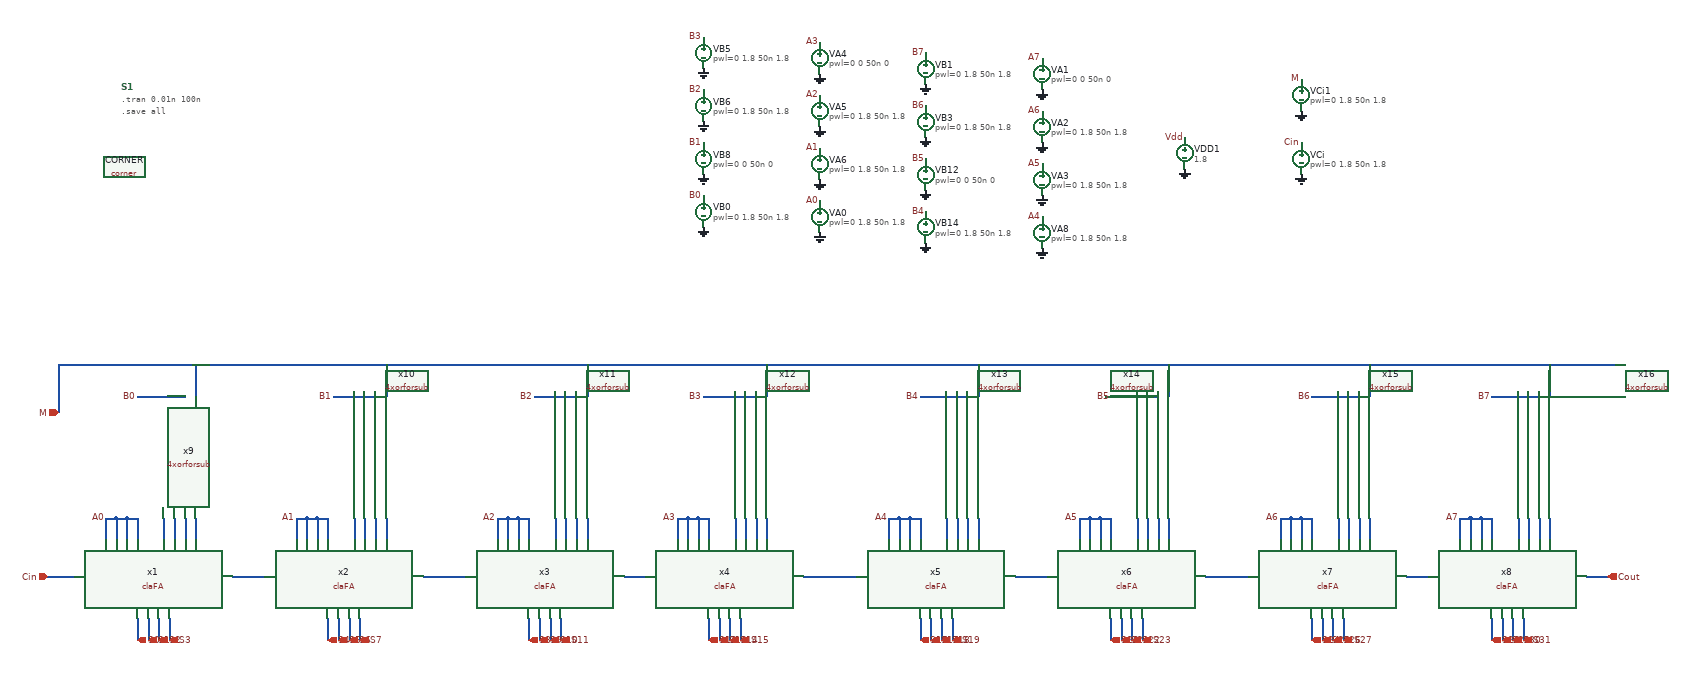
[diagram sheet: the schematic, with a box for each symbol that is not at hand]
v {xschem version=3.4.5 file_version=1.2
}
G {}
K {}
V {}
S {}
E {}
B 2 470 -1465 1270 -1065 {flags=graph
y1=0
y2=2
ypos1=-0.67313425
ypos2=1.3268657

subdivy=1
unity=1
x1=-3.0826129e-09
x2=9.6917371e-08


xlabmag=1.0
ylabmag=1.0


dataset=-1
unitx=1
logx=0
logy=0
divx=10
divy=5
subdivx=1
digital=1



color="11 11 11"
node="a;a0,a,a,a,a1,a1,a1,a1,a2,a2,a2,a2,a3,a3,a3,a3,a4,a4,a4,a4,a5,a5,a5,a5,a6,a6,a6,a6,a7,a7,a7,a7
b;b0,b0,b0,b0,b1,b1,b1,b1,b2,b2,b2,b2,b4,b3,b3,b3,b4,b4,b4,b4,b5,b5,b5,b5,b6,b6,b6,b6,b7,b7,b7,b7
sub;s0,s1,s2,s3,s4,s5,s6,s7,s8,s9,s10,s11,s12,s13,s14,s15,s16,s17,s18,s19,s20,s21,s22,s23,s24,s25,s26,s27,s28,s29,s30,s31"}
B 2 480 -2035 1280 -1635 {flags=graph
y1=0
y2=2
ypos1=1.1268657
ypos2=3.1268657

subdivy=1
unity=1
x1=-3.0826129e-09
x2=9.6917371e-08


xlabmag=1.0
ylabmag=1.0


dataset=-1
unitx=1
logx=0
logy=0
divx=10
divy=5
subdivx=1
digital=1




color="4 4 4 4 4 4 4 4 4 4 4 4 4 4 4 4 4 4 4 4 4 4 4 4 4 4 4 4 4 4 4 4"
node="a7
a7
a7
a7
a6
a6
a6
a6
a5
a5
a5
a5
a4
a4
a4
a4
a3
a3
a3
a3
a2
a2
a2
a2
a1
a1
a1
a1
a0
a0
a0
a0"}
N 460 -450 520 -450 {
lab=#net1}
N 820 -450 900 -450 {
lab=#net2}
N 1200 -450 1240 -450 {
lab=#net3}
N 1540 -450 1600 -450 {
lab=#net4}
N 110 -450 160 -450 {
lab=Cin}
N 220 -560 220 -520 {
lab=A0}
N 240 -560 240 -520 {
lab=A0}
N 260 -560 260 -520 {
lab=A0}
N 280 -560 280 -520 {
lab=A0}
N 330 -560 330 -520 {
lab=#net5}
N 350 -560 350 -520 {
lab=#net6}
N 370 -560 370 -520 {
lab=#net7}
N 390 -560 390 -520 {
lab=#net8}
N 580 -560 580 -520 {
lab=A1}
N 600 -560 600 -520 {
lab=A1}
N 620 -560 620 -520 {
lab=A1}
N 640 -560 640 -520 {
lab=A1}
N 690 -560 690 -520 {
lab=#net9}
N 710 -560 710 -520 {
lab=#net10}
N 730 -560 730 -520 {
lab=#net11}
N 750 -560 750 -520 {
lab=#net12}
N 640 -370 640 -330 {
lab=S4}
N 660 -370 660 -330 {
lab=S5}
N 680 -370 680 -330 {
lab=S6}
N 700 -370 700 -330 {
lab=S7}
N 280 -370 280 -330 {
lab=S0}
N 300 -370 300 -330 {
lab=S1}
N 320 -370 320 -330 {
lab=S2}
N 340 -370 340 -330 {
lab=S3}
N 960 -560 960 -520 {
lab=A2}
N 980 -560 980 -520 {
lab=A2}
N 1000 -560 1000 -520 {
lab=A2}
N 1020 -560 1020 -520 {
lab=A2}
N 1070 -560 1070 -520 {
lab=#net13}
N 1090 -560 1090 -520 {
lab=#net14}
N 1110 -560 1110 -520 {
lab=#net15}
N 1130 -560 1130 -520 {
lab=#net16}
N 1300 -560 1300 -520 {
lab=A3}
N 1320 -560 1320 -520 {
lab=A3}
N 1340 -560 1340 -520 {
lab=A3}
N 1360 -560 1360 -520 {
lab=A3}
N 1410 -560 1410 -520 {
lab=#net17}
N 1430 -560 1430 -520 {
lab=#net18}
N 1450 -560 1450 -520 {
lab=#net19}
N 1470 -560 1470 -520 {
lab=#net20}
N 1020 -370 1020 -330 {
lab=S8}
N 1040 -370 1040 -330 {
lab=S9}
N 1060 -370 1060 -330 {
lab=S10}
N 1080 -370 1080 -330 {
lab=S11}
N 1360 -370 1360 -330 {
lab=S12}
N 1380 -370 1380 -330 {
lab=S13}
N 1400 -370 1400 -330 {
lab=S14}
N 1420 -370 1420 -330 {
lab=S15}
N 260 -560 280 -560 {
lab=A0}
N 240 -560 260 -560 {
lab=A0}
N 220 -560 240 -560 {
lab=A0}
N 580 -560 600 -560 {
lab=A1}
N 600 -560 620 -560 {
lab=A1}
N 620 -560 640 -560 {
lab=A1}
N 960 -560 980 -560 {
lab=A2}
N 980 -560 1000 -560 {
lab=A2}
N 1000 -560 1020 -560 {
lab=A2}
N 1300 -560 1320 -560 {
lab=A3}
N 1320 -560 1340 -560 {
lab=A3}
N 1340 -560 1360 -560 {
lab=A3}
N 1940 -450 2000 -450 {
lab=#net21}
N 2300 -450 2380 -450 {
lab=#net22}
N 2680 -450 2720 -450 {
lab=#net23}
N 1700 -560 1700 -520 {
lab=A4}
N 1720 -560 1720 -520 {
lab=A4}
N 1740 -560 1740 -520 {
lab=A4}
N 1760 -560 1760 -520 {
lab=A4}
N 1810 -560 1810 -520 {
lab=#net24}
N 1830 -560 1830 -520 {
lab=#net25}
N 1850 -560 1850 -520 {
lab=#net26}
N 1870 -560 1870 -520 {
lab=#net27}
N 2060 -560 2060 -520 {
lab=A5}
N 2080 -560 2080 -520 {
lab=A5}
N 2100 -560 2100 -520 {
lab=A5}
N 2120 -560 2120 -520 {
lab=A5}
N 2170 -560 2170 -520 {
lab=#net28}
N 2190 -560 2190 -520 {
lab=#net29}
N 2210 -560 2210 -520 {
lab=#net30}
N 2230 -560 2230 -520 {
lab=#net31}
N 2120 -370 2120 -330 {
lab=S20}
N 2140 -370 2140 -330 {
lab=S21}
N 2160 -370 2160 -330 {
lab=S22}
N 2180 -370 2180 -330 {
lab=S23}
N 1760 -370 1760 -330 {
lab=S16}
N 1780 -370 1780 -330 {
lab=S17}
N 1800 -370 1800 -330 {
lab=S18}
N 1820 -370 1820 -330 {
lab=S19}
N 2440 -560 2440 -520 {
lab=A6}
N 2460 -560 2460 -520 {
lab=A6}
N 2480 -560 2480 -520 {
lab=A6}
N 2500 -560 2500 -520 {
lab=A6}
N 2550 -560 2550 -520 {
lab=#net32}
N 2570 -560 2570 -520 {
lab=#net33}
N 2590 -560 2590 -520 {
lab=#net34}
N 2610 -560 2610 -520 {
lab=#net35}
N 2780 -560 2780 -520 {
lab=A7}
N 2800 -560 2800 -520 {
lab=A7}
N 2820 -560 2820 -520 {
lab=A7}
N 2840 -560 2840 -520 {
lab=A7}
N 2890 -560 2890 -520 {
lab=#net36}
N 2910 -560 2910 -520 {
lab=#net37}
N 2930 -560 2930 -520 {
lab=#net38}
N 2950 -560 2950 -520 {
lab=#net39}
N 2500 -370 2500 -330 {
lab=S24}
N 2520 -370 2520 -330 {
lab=S25}
N 2540 -370 2540 -330 {
lab=S26}
N 2560 -370 2560 -330 {
lab=S27}
N 2840 -370 2840 -330 {
lab=S28}
N 2860 -370 2860 -330 {
lab=S29}
N 2880 -370 2880 -330 {
lab=S30}
N 2900 -370 2900 -330 {
lab=S31}
N 1740 -560 1760 -560 {
lab=A4}
N 1720 -560 1740 -560 {
lab=A4}
N 1700 -560 1720 -560 {
lab=A4}
N 2060 -560 2080 -560 {
lab=A5}
N 2080 -560 2100 -560 {
lab=A5}
N 2100 -560 2120 -560 {
lab=A5}
N 2440 -560 2460 -560 {
lab=A6}
N 2460 -560 2480 -560 {
lab=A6}
N 2480 -560 2500 -560 {
lab=A6}
N 2780 -560 2800 -560 {
lab=A7}
N 2800 -560 2820 -560 {
lab=A7}
N 2820 -560 2840 -560 {
lab=A7}
N 3020 -450 3060 -450 {
lab=Cout}
N 1600 -450 1640 -450 {
lab=#net4}
N 384 -850 3074 -850 {
lab=M}
N 130 -850 130 -760 {
lab=M}
N 130 -850 380 -850 {
lab=M}
N 380 -850 390 -850 {
lab=M}
N 2950 -850 2950 -790 {
lab=M}
N 2610 -850 2610 -790 {
lab=M}
N 2230 -850 2230 -790 {
lab=M}
N 1870 -850 1870 -790 {
lab=M}
N 1130 -850 1130 -790 {
lab=M}
N 750 -850 750 -790 {
lab=M}
N 390 -850 390 -790 {
lab=M}
N 350 -790 370 -790 {
lab=B0}
N 330 -790 350 -790 {
lab=B0}
N 310 -790 330 -790 {
lab=B0}
N 280 -790 310 -790 {
lab=B0}
N 710 -790 730 -790 {
lab=B1}
N 690 -790 710 -790 {
lab=B1}
N 650 -790 690 -790 {
lab=B1}
N 1030 -790 1110 -790 {
lab=B2}
N 1470 -850 1470 -790 {
lab=M}
N 1350 -790 1450 -790 {
lab=B3}
N 1760 -790 1850 -790 {
lab=B4}
N 2110 -790 2210 -790 {
lab=B5}
N 2500 -790 2590 -790 {
lab=B6}
N 2840 -790 2930 -790 {
lab=B7}
C {claFA.sym} 310 -430 0 0 {name=x1}
C {claFA.sym} 670 -430 0 0 {name=x2}
C {claFA.sym} 1050 -430 0 0 {name=x3}
C {claFA.sym} 1390 -430 0 0 {name=x4}
C {devices/lab_pin.sym} 220 -560 0 0 {name=p1 sig_type=std_logic lab=A0}
C {devices/lab_pin.sym} 580 -560 0 0 {name=p2 sig_type=std_logic lab=A1}
C {devices/lab_pin.sym} 960 -560 0 0 {name=p3 sig_type=std_logic lab=A2}
C {devices/lab_pin.sym} 1300 -560 0 0 {name=p4 sig_type=std_logic lab=A3}
C {devices/lab_pin.sym} 280 -790 0 0 {name=p5 sig_type=std_logic lab=B0}
C {devices/lab_pin.sym} 650 -790 0 0 {name=p6 sig_type=std_logic lab=B1}
C {devices/lab_pin.sym} 1030 -790 0 0 {name=p7 sig_type=std_logic lab=B2}
C {devices/ipin.sym} 110 -450 0 0 {name=p9 sig_type=std_logic lab=Cin}
C {devices/opin.sym} 3060 -450 0 0 {name=p10 sig_type=std_logic lab=Cout}
C {devices/opin.sym} 280 -330 1 0 {name=p11 sig_type=std_logic lab=S0}
C {devices/opin.sym} 300 -330 1 0 {name=p12 sig_type=std_logic lab=S1}
C {devices/opin.sym} 320 -330 1 0 {name=p13 sig_type=std_logic lab=S2}
C {devices/opin.sym} 340 -330 1 0 {name=p14 sig_type=std_logic lab=S3}
C {devices/opin.sym} 640 -330 1 0 {name=p15 sig_type=std_logic lab=S4}
C {devices/opin.sym} 660 -330 1 0 {name=p16 sig_type=std_logic lab=S5}
C {devices/opin.sym} 680 -330 1 0 {name=p17 sig_type=std_logic lab=S6}
C {devices/opin.sym} 700 -330 1 0 {name=p18 sig_type=std_logic lab=S7}
C {devices/opin.sym} 1020 -330 1 0 {name=p19 sig_type=std_logic lab=S8}
C {devices/opin.sym} 1040 -330 1 0 {name=p20 sig_type=std_logic lab=S9}
C {devices/opin.sym} 1060 -330 1 0 {name=p21 sig_type=std_logic lab=S10}
C {devices/opin.sym} 1080 -330 1 0 {name=p22 sig_type=std_logic lab=S11}
C {devices/opin.sym} 1360 -330 1 0 {name=p23 sig_type=std_logic lab=S12}
C {devices/opin.sym} 1380 -330 1 0 {name=p24 sig_type=std_logic lab=S13}
C {devices/opin.sym} 1400 -330 1 0 {name=p25 sig_type=std_logic lab=S14}
C {devices/opin.sym} 1420 -330 1 0 {name=p26 sig_type=std_logic lab=S15}
C {devices/code_shown.sym} 250 -1375 0 0 {name=S1 only_toplevel=false value=".tran 0.01n 100n
.save all"}
C {sky130_fd_pr/corner.sym} 255 -1225 0 0 {name=CORNER only_toplevel=true corner=tt}
C {devices/vsource.sym} 1570 -1430 0 0 {name=VA4 value="pwl=0 0 50n 0" savecurrent=false}
C {devices/lab_pin.sym} 1570 -1460 0 0 {name=p38 sig_type=std_logic lab=A3}
C {devices/vsource.sym} 1570 -1330 0 0 {name=VA5 value="pwl=0 1.8 50n 1.8 " savecurrent=false}
C {devices/lab_pin.sym} 1570 -1360 0 0 {name=p39 sig_type=std_logic lab=A2}
C {devices/vsource.sym} 1570 -1230 0 0 {name=VA6 value="pwl=0 1.8 50n 1.8 " savecurrent=false}
C {devices/lab_pin.sym} 1570 -1260 0 0 {name=p40 sig_type=std_logic lab=A1}
C {devices/vsource.sym} 1570 -1130 0 0 {name=VA0 value="pwl=0 1.8 50n 1.8" savecurrent=false}
C {devices/lab_pin.sym} 1570 -1160 0 0 {name=VA7 sig_type=std_logic lab=A0}
C {devices/vsource.sym} 1350 -1440 0 0 {name=VB5 value="pwl=0 1.8 50n 1.8 " savecurrent=false}
C {devices/lab_pin.sym} 1350 -1470 0 0 {name=VB4 sig_type=std_logic lab=B3}
C {devices/vsource.sym} 1350 -1340 0 0 {name=VB6 value="pwl=0 1.8 50n 1.8 " savecurrent=false}
C {devices/lab_pin.sym} 1350 -1370 0 0 {name=VB7 sig_type=std_logic lab=B2}
C {devices/vsource.sym} 1350 -1240 0 0 {name=VB8 value="pwl=0 0 50n 0 " savecurrent=false}
C {devices/lab_pin.sym} 1350 -1270 0 0 {name=VB9 sig_type=std_logic lab=B1}
C {devices/vsource.sym} 1350 -1140 0 0 {name=VB0 value="pwl=0 1.8 50n 1.8" savecurrent=false}
C {devices/lab_pin.sym} 1350 -1170 0 0 {name=VB10 sig_type=std_logic lab=B0}
C {devices/gnd.sym} 1570 -1100 0 0 {name=l7 lab=GND}
C {devices/gnd.sym} 1350 -1110 0 0 {name=l8 lab=GND}
C {devices/gnd.sym} 1570 -1200 0 0 {name=l15 lab=GND}
C {devices/gnd.sym} 1350 -1210 0 0 {name=l16 lab=GND}
C {devices/gnd.sym} 1570 -1300 0 0 {name=l17 lab=GND}
C {devices/gnd.sym} 1350 -1310 0 0 {name=l18 lab=GND}
C {devices/gnd.sym} 1350 -1410 0 0 {name=l19 lab=GND}
C {devices/gnd.sym} 1570 -1400 0 0 {name=l20 lab=GND}
C {devices/vsource.sym} 2480 -1240 0 0 {name=VCi value="pwl=0 1.8 50n 1.8 " savecurrent=false}
C {devices/lab_pin.sym} 2480 -1270 0 0 {name=Ci1 sig_type=std_logic lab=Cin}
C {devices/gnd.sym} 2480 -1210 0 0 {name=Ci2 lab=GND}
C {devices/vsource.sym} 2260 -1250 0 0 {name=VDD1 value=1.8 savecurrent=false}
C {devices/lab_pin.sym} 2260 -1280 0 0 {name=Ci3 sig_type=std_logic lab=Vdd}
C {devices/gnd.sym} 2260 -1220 0 0 {name=Ci4 lab=GND}
C {claFA.sym} 1790 -430 0 0 {name=x5}
C {claFA.sym} 2150 -430 0 0 {name=x6}
C {claFA.sym} 2530 -430 0 0 {name=x7}
C {claFA.sym} 2870 -430 0 0 {name=x8}
C {devices/lab_pin.sym} 1700 -560 0 0 {name=p27 sig_type=std_logic lab=A4}
C {devices/lab_pin.sym} 2060 -560 0 0 {name=p28 sig_type=std_logic lab=A5}
C {devices/lab_pin.sym} 2440 -560 0 0 {name=p29 sig_type=std_logic lab=A6}
C {devices/lab_pin.sym} 2780 -560 0 0 {name=p30 sig_type=std_logic lab=A7}
C {devices/opin.sym} 1760 -330 1 0 {name=p35 sig_type=std_logic lab=S16}
C {devices/opin.sym} 1780 -330 1 0 {name=p36 sig_type=std_logic lab=S17}
C {devices/opin.sym} 1800 -330 1 0 {name=p37 sig_type=std_logic lab=S18}
C {devices/opin.sym} 1820 -330 1 0 {name=p41 sig_type=std_logic lab=S19}
C {devices/opin.sym} 2120 -330 1 0 {name=p42 sig_type=std_logic lab=S20}
C {devices/opin.sym} 2140 -330 1 0 {name=p43 sig_type=std_logic lab=S21}
C {devices/opin.sym} 2160 -330 1 0 {name=p44 sig_type=std_logic lab=S22}
C {devices/opin.sym} 2180 -330 1 0 {name=p45 sig_type=std_logic lab=S23}
C {devices/opin.sym} 2500 -330 1 0 {name=p46 sig_type=std_logic lab=S24}
C {devices/opin.sym} 2520 -330 1 0 {name=p47 sig_type=std_logic lab=S25}
C {devices/opin.sym} 2540 -330 1 0 {name=p48 sig_type=std_logic lab=S26}
C {devices/opin.sym} 2560 -330 1 0 {name=p49 sig_type=std_logic lab=S27}
C {devices/opin.sym} 2840 -330 1 0 {name=p50 sig_type=std_logic lab=S28}
C {devices/opin.sym} 2860 -330 1 0 {name=p51 sig_type=std_logic lab=S29}
C {devices/opin.sym} 2880 -330 1 0 {name=p52 sig_type=std_logic lab=S30}
C {devices/opin.sym} 2900 -330 1 0 {name=p53 sig_type=std_logic lab=S31}
C {devices/vsource.sym} 1990 -1400 0 0 {name=VA1 value="pwl=0 0 50n 0" savecurrent=false}
C {devices/lab_pin.sym} 1990 -1430 0 0 {name=p54 sig_type=std_logic lab=A7}
C {devices/vsource.sym} 1990 -1300 0 0 {name=VA2 value="pwl=0 1.8 50n 1.8 " savecurrent=false}
C {devices/lab_pin.sym} 1990 -1330 0 0 {name=p55 sig_type=std_logic lab=A6}
C {devices/vsource.sym} 1990 -1200 0 0 {name=VA3 value="pwl=0 1.8 50n 1.8 " savecurrent=false}
C {devices/lab_pin.sym} 1990 -1230 0 0 {name=p56 sig_type=std_logic lab=A5}
C {devices/vsource.sym} 1990 -1100 0 0 {name=VA8 value="pwl=0 1.8 50n 1.8" savecurrent=false}
C {devices/lab_pin.sym} 1990 -1130 0 0 {name=VA9 sig_type=std_logic lab=A4}
C {devices/vsource.sym} 1770 -1410 0 0 {name=VB1 value="pwl=0 1.8 50n 1.8 " savecurrent=false}
C {devices/lab_pin.sym} 1770 -1440 0 0 {name=VB2 sig_type=std_logic lab=B7}
C {devices/vsource.sym} 1770 -1310 0 0 {name=VB3 value="pwl=0 1.8 50n 1.8 " savecurrent=false}
C {devices/lab_pin.sym} 1770 -1340 0 0 {name=VB11 sig_type=std_logic lab=B6}
C {devices/vsource.sym} 1770 -1210 0 0 {name=VB12 value="pwl=0 0 50n 0 " savecurrent=false}
C {devices/lab_pin.sym} 1770 -1240 0 0 {name=VB13 sig_type=std_logic lab=B5}
C {devices/vsource.sym} 1770 -1110 0 0 {name=VB14 value="pwl=0 1.8 50n 1.8" savecurrent=false}
C {devices/lab_pin.sym} 1770 -1140 0 0 {name=VB15 sig_type=std_logic lab=B4}
C {devices/gnd.sym} 1990 -1070 0 0 {name=l1 lab=GND}
C {devices/gnd.sym} 1770 -1080 0 0 {name=l2 lab=GND}
C {devices/gnd.sym} 1990 -1170 0 0 {name=l3 lab=GND}
C {devices/gnd.sym} 1770 -1180 0 0 {name=l4 lab=GND}
C {devices/gnd.sym} 1990 -1270 0 0 {name=l5 lab=GND}
C {devices/gnd.sym} 1770 -1280 0 0 {name=l6 lab=GND}
C {devices/gnd.sym} 1770 -1380 0 0 {name=l9 lab=GND}
C {devices/gnd.sym} 1990 -1370 0 0 {name=l10 lab=GND}
C {4xorforsub.sym} 350 -640 1 0 {name=x9}
C {4xorforsub.sym} 710 -640 1 0 {name=x10}
C {4xorforsub.sym} 1090 -640 1 0 {name=x11}
C {4xorforsub.sym} 1430 -640 1 0 {name=x12}
C {4xorforsub.sym} 1830 -640 1 0 {name=x13}
C {4xorforsub.sym} 2190 -640 1 0 {name=x14}
C {4xorforsub.sym} 2570 -640 1 0 {name=x15}
C {4xorforsub.sym} 2910 -640 1 0 {name=x16}
C {devices/lab_pin.sym} 1350 -790 0 0 {name=p8 sig_type=std_logic lab=B3}
C {devices/lab_pin.sym} 1760 -790 0 0 {name=p31 sig_type=std_logic lab=B4}
C {devices/lab_pin.sym} 2120 -790 0 0 {name=p32 sig_type=std_logic lab=B5}
C {devices/lab_pin.sym} 2500 -790 0 0 {name=p33 sig_type=std_logic lab=B6}
C {devices/lab_pin.sym} 2840 -790 0 0 {name=p34 sig_type=std_logic lab=B7}
C {devices/vsource.sym} 2480 -1360 0 0 {name=VCi1 value="pwl=0 1.8 50n 1.8 " savecurrent=false}
C {devices/lab_pin.sym} 2480 -1390 0 0 {name=Ci5 sig_type=std_logic lab=M}
C {devices/gnd.sym} 2480 -1330 0 0 {name=Ci6 lab=GND}
C {devices/ipin.sym} 130 -760 0 0 {name=p57 sig_type=std_logic lab=M}
